VERSION 5.8 ;
BUSBITCHARS "[]" ;
DIVIDERCHAR "/" ;

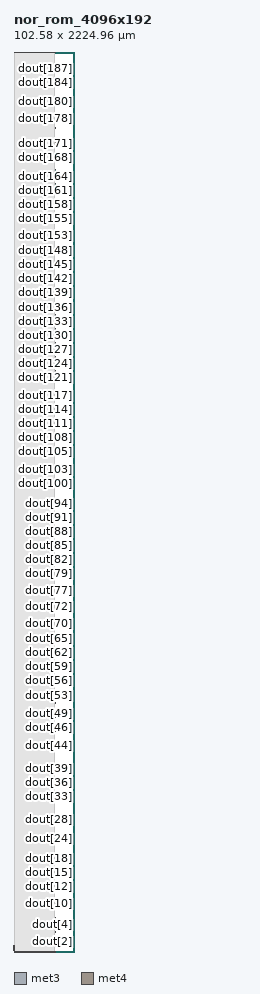
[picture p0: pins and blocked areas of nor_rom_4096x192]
MACRO nor_rom_4096x192
  CLASS BLOCK ;
  ORIGIN 0 0 ;
  SIZE 102.580 BY 2224.960 ;
  SYMMETRY X Y ;

  PIN clk
    DIRECTION INPUT ;
    USE CLOCK ;
    PORT
      LAYER met3 ;
        RECT -0.500 3.000 0.500 3.280 ;
    END
  END clk

  PIN ce
    DIRECTION INPUT ;
    USE SIGNAL ;
    PORT
      LAYER met3 ;
        RECT -0.500 4.000 0.500 4.280 ;
    END
  END ce

  PIN addr[0]
    DIRECTION INPUT ;
    USE SIGNAL ;
    PORT
      LAYER met3 ;
        RECT -0.500 5.000 0.500 5.280 ;
    END
  END addr[0]

  PIN addr[1]
    DIRECTION INPUT ;
    USE SIGNAL ;
    PORT
      LAYER met3 ;
        RECT -0.500 6.000 0.500 6.280 ;
    END
  END addr[1]

  PIN addr[2]
    DIRECTION INPUT ;
    USE SIGNAL ;
    PORT
      LAYER met3 ;
        RECT -0.500 7.000 0.500 7.280 ;
    END
  END addr[2]

  PIN addr[3]
    DIRECTION INPUT ;
    USE SIGNAL ;
    PORT
      LAYER met3 ;
        RECT -0.500 8.000 0.500 8.280 ;
    END
  END addr[3]

  PIN addr[4]
    DIRECTION INPUT ;
    USE SIGNAL ;
    PORT
      LAYER met3 ;
        RECT -0.500 9.000 0.500 9.280 ;
    END
  END addr[4]

  PIN addr[5]
    DIRECTION INPUT ;
    USE SIGNAL ;
    PORT
      LAYER met3 ;
        RECT -0.500 10.000 0.500 10.280 ;
    END
  END addr[5]

  PIN addr[6]
    DIRECTION INPUT ;
    USE SIGNAL ;
    PORT
      LAYER met3 ;
        RECT -0.500 11.000 0.500 11.280 ;
    END
  END addr[6]

  PIN addr[7]
    DIRECTION INPUT ;
    USE SIGNAL ;
    PORT
      LAYER met3 ;
        RECT -0.500 12.000 0.500 12.280 ;
    END
  END addr[7]

  PIN addr[8]
    DIRECTION INPUT ;
    USE SIGNAL ;
    PORT
      LAYER met3 ;
        RECT -0.500 13.000 0.500 13.280 ;
    END
  END addr[8]

  PIN addr[9]
    DIRECTION INPUT ;
    USE SIGNAL ;
    PORT
      LAYER met3 ;
        RECT -0.500 14.000 0.500 14.280 ;
    END
  END addr[9]

  PIN addr[10]
    DIRECTION INPUT ;
    USE SIGNAL ;
    PORT
      LAYER met3 ;
        RECT -0.500 15.000 0.500 15.280 ;
    END
  END addr[10]

  PIN addr[11]
    DIRECTION INPUT ;
    USE SIGNAL ;
    PORT
      LAYER met3 ;
        RECT -0.500 16.000 0.500 16.280 ;
    END
  END addr[11]

  PIN dout[0]
    DIRECTION OUTPUT ;
    USE SIGNAL ;
    PORT
      LAYER met3 ;
        RECT 102.080 3.000 103.080 3.280 ;
    END
  END dout[0]

  PIN dout[1]
    DIRECTION OUTPUT ;
    USE SIGNAL ;
    PORT
      LAYER met3 ;
        RECT 102.080 14.557 103.080 14.837 ;
    END
  END dout[1]

  PIN dout[2]
    DIRECTION OUTPUT ;
    USE SIGNAL ;
    PORT
      LAYER met3 ;
        RECT 102.080 26.114 103.080 26.394 ;
    END
  END dout[2]

  PIN dout[3]
    DIRECTION OUTPUT ;
    USE SIGNAL ;
    PORT
      LAYER met3 ;
        RECT 102.080 37.671 103.080 37.951 ;
    END
  END dout[3]

  PIN dout[4]
    DIRECTION OUTPUT ;
    USE SIGNAL ;
    PORT
      LAYER met3 ;
        RECT 102.080 49.228 103.080 49.508 ;
    END
  END dout[4]

  PIN dout[5]
    DIRECTION OUTPUT ;
    USE SIGNAL ;
    PORT
      LAYER met3 ;
        RECT 102.080 60.785 103.080 61.065 ;
    END
  END dout[5]

  PIN dout[6]
    DIRECTION OUTPUT ;
    USE SIGNAL ;
    PORT
      LAYER met3 ;
        RECT 102.080 72.343 103.080 72.623 ;
    END
  END dout[6]

  PIN dout[7]
    DIRECTION OUTPUT ;
    USE SIGNAL ;
    PORT
      LAYER met3 ;
        RECT 102.080 83.900 103.080 84.180 ;
    END
  END dout[7]

  PIN dout[8]
    DIRECTION OUTPUT ;
    USE SIGNAL ;
    PORT
      LAYER met3 ;
        RECT 102.080 95.457 103.080 95.737 ;
    END
  END dout[8]

  PIN dout[9]
    DIRECTION OUTPUT ;
    USE SIGNAL ;
    PORT
      LAYER met3 ;
        RECT 102.080 107.014 103.080 107.294 ;
    END
  END dout[9]

  PIN dout[10]
    DIRECTION OUTPUT ;
    USE SIGNAL ;
    PORT
      LAYER met3 ;
        RECT 102.080 118.571 103.080 118.851 ;
    END
  END dout[10]

  PIN dout[11]
    DIRECTION OUTPUT ;
    USE SIGNAL ;
    PORT
      LAYER met3 ;
        RECT 102.080 130.128 103.080 130.408 ;
    END
  END dout[11]

  PIN dout[12]
    DIRECTION OUTPUT ;
    USE SIGNAL ;
    PORT
      LAYER met3 ;
        RECT 102.080 141.685 103.080 141.965 ;
    END
  END dout[12]

  PIN dout[13]
    DIRECTION OUTPUT ;
    USE SIGNAL ;
    PORT
      LAYER met3 ;
        RECT 102.080 153.242 103.080 153.522 ;
    END
  END dout[13]

  PIN dout[14]
    DIRECTION OUTPUT ;
    USE SIGNAL ;
    PORT
      LAYER met3 ;
        RECT 102.080 164.799 103.080 165.079 ;
    END
  END dout[14]

  PIN dout[15]
    DIRECTION OUTPUT ;
    USE SIGNAL ;
    PORT
      LAYER met3 ;
        RECT 102.080 176.356 103.080 176.636 ;
    END
  END dout[15]

  PIN dout[16]
    DIRECTION OUTPUT ;
    USE SIGNAL ;
    PORT
      LAYER met3 ;
        RECT 102.080 187.913 103.080 188.193 ;
    END
  END dout[16]

  PIN dout[17]
    DIRECTION OUTPUT ;
    USE SIGNAL ;
    PORT
      LAYER met3 ;
        RECT 102.080 199.470 103.080 199.750 ;
    END
  END dout[17]

  PIN dout[18]
    DIRECTION OUTPUT ;
    USE SIGNAL ;
    PORT
      LAYER met3 ;
        RECT 102.080 211.028 103.080 211.308 ;
    END
  END dout[18]

  PIN dout[19]
    DIRECTION OUTPUT ;
    USE SIGNAL ;
    PORT
      LAYER met3 ;
        RECT 102.080 222.585 103.080 222.865 ;
    END
  END dout[19]

  PIN dout[20]
    DIRECTION OUTPUT ;
    USE SIGNAL ;
    PORT
      LAYER met3 ;
        RECT 102.080 234.142 103.080 234.422 ;
    END
  END dout[20]

  PIN dout[21]
    DIRECTION OUTPUT ;
    USE SIGNAL ;
    PORT
      LAYER met3 ;
        RECT 102.080 245.699 103.080 245.979 ;
    END
  END dout[21]

  PIN dout[22]
    DIRECTION OUTPUT ;
    USE SIGNAL ;
    PORT
      LAYER met3 ;
        RECT 102.080 257.256 103.080 257.536 ;
    END
  END dout[22]

  PIN dout[23]
    DIRECTION OUTPUT ;
    USE SIGNAL ;
    PORT
      LAYER met3 ;
        RECT 102.080 268.813 103.080 269.093 ;
    END
  END dout[23]

  PIN dout[24]
    DIRECTION OUTPUT ;
    USE SIGNAL ;
    PORT
      LAYER met3 ;
        RECT 102.080 280.370 103.080 280.650 ;
    END
  END dout[24]

  PIN dout[25]
    DIRECTION OUTPUT ;
    USE SIGNAL ;
    PORT
      LAYER met3 ;
        RECT 102.080 291.927 103.080 292.207 ;
    END
  END dout[25]

  PIN dout[26]
    DIRECTION OUTPUT ;
    USE SIGNAL ;
    PORT
      LAYER met3 ;
        RECT 102.080 303.484 103.080 303.764 ;
    END
  END dout[26]

  PIN dout[27]
    DIRECTION OUTPUT ;
    USE SIGNAL ;
    PORT
      LAYER met3 ;
        RECT 102.080 315.041 103.080 315.321 ;
    END
  END dout[27]

  PIN dout[28]
    DIRECTION OUTPUT ;
    USE SIGNAL ;
    PORT
      LAYER met3 ;
        RECT 102.080 326.598 103.080 326.878 ;
    END
  END dout[28]

  PIN dout[29]
    DIRECTION OUTPUT ;
    USE SIGNAL ;
    PORT
      LAYER met3 ;
        RECT 102.080 338.155 103.080 338.435 ;
    END
  END dout[29]

  PIN dout[30]
    DIRECTION OUTPUT ;
    USE SIGNAL ;
    PORT
      LAYER met3 ;
        RECT 102.080 349.712 103.080 349.992 ;
    END
  END dout[30]

  PIN dout[31]
    DIRECTION OUTPUT ;
    USE SIGNAL ;
    PORT
      LAYER met3 ;
        RECT 102.080 361.270 103.080 361.550 ;
    END
  END dout[31]

  PIN dout[32]
    DIRECTION OUTPUT ;
    USE SIGNAL ;
    PORT
      LAYER met3 ;
        RECT 102.080 372.827 103.080 373.107 ;
    END
  END dout[32]

  PIN dout[33]
    DIRECTION OUTPUT ;
    USE SIGNAL ;
    PORT
      LAYER met3 ;
        RECT 102.080 384.384 103.080 384.664 ;
    END
  END dout[33]

  PIN dout[34]
    DIRECTION OUTPUT ;
    USE SIGNAL ;
    PORT
      LAYER met3 ;
        RECT 102.080 395.941 103.080 396.221 ;
    END
  END dout[34]

  PIN dout[35]
    DIRECTION OUTPUT ;
    USE SIGNAL ;
    PORT
      LAYER met3 ;
        RECT 102.080 407.498 103.080 407.778 ;
    END
  END dout[35]

  PIN dout[36]
    DIRECTION OUTPUT ;
    USE SIGNAL ;
    PORT
      LAYER met3 ;
        RECT 102.080 419.055 103.080 419.335 ;
    END
  END dout[36]

  PIN dout[37]
    DIRECTION OUTPUT ;
    USE SIGNAL ;
    PORT
      LAYER met3 ;
        RECT 102.080 430.612 103.080 430.892 ;
    END
  END dout[37]

  PIN dout[38]
    DIRECTION OUTPUT ;
    USE SIGNAL ;
    PORT
      LAYER met3 ;
        RECT 102.080 442.169 103.080 442.449 ;
    END
  END dout[38]

  PIN dout[39]
    DIRECTION OUTPUT ;
    USE SIGNAL ;
    PORT
      LAYER met3 ;
        RECT 102.080 453.726 103.080 454.006 ;
    END
  END dout[39]

  PIN dout[40]
    DIRECTION OUTPUT ;
    USE SIGNAL ;
    PORT
      LAYER met3 ;
        RECT 102.080 465.283 103.080 465.563 ;
    END
  END dout[40]

  PIN dout[41]
    DIRECTION OUTPUT ;
    USE SIGNAL ;
    PORT
      LAYER met3 ;
        RECT 102.080 476.840 103.080 477.120 ;
    END
  END dout[41]

  PIN dout[42]
    DIRECTION OUTPUT ;
    USE SIGNAL ;
    PORT
      LAYER met3 ;
        RECT 102.080 488.397 103.080 488.677 ;
    END
  END dout[42]

  PIN dout[43]
    DIRECTION OUTPUT ;
    USE SIGNAL ;
    PORT
      LAYER met3 ;
        RECT 102.080 499.955 103.080 500.235 ;
    END
  END dout[43]

  PIN dout[44]
    DIRECTION OUTPUT ;
    USE SIGNAL ;
    PORT
      LAYER met3 ;
        RECT 102.080 511.512 103.080 511.792 ;
    END
  END dout[44]

  PIN dout[45]
    DIRECTION OUTPUT ;
    USE SIGNAL ;
    PORT
      LAYER met3 ;
        RECT 102.080 523.069 103.080 523.349 ;
    END
  END dout[45]

  PIN dout[46]
    DIRECTION OUTPUT ;
    USE SIGNAL ;
    PORT
      LAYER met3 ;
        RECT 102.080 534.626 103.080 534.906 ;
    END
  END dout[46]

  PIN dout[47]
    DIRECTION OUTPUT ;
    USE SIGNAL ;
    PORT
      LAYER met3 ;
        RECT 102.080 546.183 103.080 546.463 ;
    END
  END dout[47]

  PIN dout[48]
    DIRECTION OUTPUT ;
    USE SIGNAL ;
    PORT
      LAYER met3 ;
        RECT 102.080 557.740 103.080 558.020 ;
    END
  END dout[48]

  PIN dout[49]
    DIRECTION OUTPUT ;
    USE SIGNAL ;
    PORT
      LAYER met3 ;
        RECT 102.080 569.297 103.080 569.577 ;
    END
  END dout[49]

  PIN dout[50]
    DIRECTION OUTPUT ;
    USE SIGNAL ;
    PORT
      LAYER met3 ;
        RECT 102.080 580.854 103.080 581.134 ;
    END
  END dout[50]

  PIN dout[51]
    DIRECTION OUTPUT ;
    USE SIGNAL ;
    PORT
      LAYER met3 ;
        RECT 102.080 592.411 103.080 592.691 ;
    END
  END dout[51]

  PIN dout[52]
    DIRECTION OUTPUT ;
    USE SIGNAL ;
    PORT
      LAYER met3 ;
        RECT 102.080 603.968 103.080 604.248 ;
    END
  END dout[52]

  PIN dout[53]
    DIRECTION OUTPUT ;
    USE SIGNAL ;
    PORT
      LAYER met3 ;
        RECT 102.080 615.525 103.080 615.805 ;
    END
  END dout[53]

  PIN dout[54]
    DIRECTION OUTPUT ;
    USE SIGNAL ;
    PORT
      LAYER met3 ;
        RECT 102.080 627.082 103.080 627.362 ;
    END
  END dout[54]

  PIN dout[55]
    DIRECTION OUTPUT ;
    USE SIGNAL ;
    PORT
      LAYER met3 ;
        RECT 102.080 638.640 103.080 638.920 ;
    END
  END dout[55]

  PIN dout[56]
    DIRECTION OUTPUT ;
    USE SIGNAL ;
    PORT
      LAYER met3 ;
        RECT 102.080 650.197 103.080 650.477 ;
    END
  END dout[56]

  PIN dout[57]
    DIRECTION OUTPUT ;
    USE SIGNAL ;
    PORT
      LAYER met3 ;
        RECT 102.080 661.754 103.080 662.034 ;
    END
  END dout[57]

  PIN dout[58]
    DIRECTION OUTPUT ;
    USE SIGNAL ;
    PORT
      LAYER met3 ;
        RECT 102.080 673.311 103.080 673.591 ;
    END
  END dout[58]

  PIN dout[59]
    DIRECTION OUTPUT ;
    USE SIGNAL ;
    PORT
      LAYER met3 ;
        RECT 102.080 684.868 103.080 685.148 ;
    END
  END dout[59]

  PIN dout[60]
    DIRECTION OUTPUT ;
    USE SIGNAL ;
    PORT
      LAYER met3 ;
        RECT 102.080 696.425 103.080 696.705 ;
    END
  END dout[60]

  PIN dout[61]
    DIRECTION OUTPUT ;
    USE SIGNAL ;
    PORT
      LAYER met3 ;
        RECT 102.080 707.982 103.080 708.262 ;
    END
  END dout[61]

  PIN dout[62]
    DIRECTION OUTPUT ;
    USE SIGNAL ;
    PORT
      LAYER met3 ;
        RECT 102.080 719.539 103.080 719.819 ;
    END
  END dout[62]

  PIN dout[63]
    DIRECTION OUTPUT ;
    USE SIGNAL ;
    PORT
      LAYER met3 ;
        RECT 102.080 731.096 103.080 731.376 ;
    END
  END dout[63]

  PIN dout[64]
    DIRECTION OUTPUT ;
    USE SIGNAL ;
    PORT
      LAYER met3 ;
        RECT 102.080 742.653 103.080 742.933 ;
    END
  END dout[64]

  PIN dout[65]
    DIRECTION OUTPUT ;
    USE SIGNAL ;
    PORT
      LAYER met3 ;
        RECT 102.080 754.210 103.080 754.490 ;
    END
  END dout[65]

  PIN dout[66]
    DIRECTION OUTPUT ;
    USE SIGNAL ;
    PORT
      LAYER met3 ;
        RECT 102.080 765.767 103.080 766.047 ;
    END
  END dout[66]

  PIN dout[67]
    DIRECTION OUTPUT ;
    USE SIGNAL ;
    PORT
      LAYER met3 ;
        RECT 102.080 777.325 103.080 777.605 ;
    END
  END dout[67]

  PIN dout[68]
    DIRECTION OUTPUT ;
    USE SIGNAL ;
    PORT
      LAYER met3 ;
        RECT 102.080 788.882 103.080 789.162 ;
    END
  END dout[68]

  PIN dout[69]
    DIRECTION OUTPUT ;
    USE SIGNAL ;
    PORT
      LAYER met3 ;
        RECT 102.080 800.439 103.080 800.719 ;
    END
  END dout[69]

  PIN dout[70]
    DIRECTION OUTPUT ;
    USE SIGNAL ;
    PORT
      LAYER met3 ;
        RECT 102.080 811.996 103.080 812.276 ;
    END
  END dout[70]

  PIN dout[71]
    DIRECTION OUTPUT ;
    USE SIGNAL ;
    PORT
      LAYER met3 ;
        RECT 102.080 823.553 103.080 823.833 ;
    END
  END dout[71]

  PIN dout[72]
    DIRECTION OUTPUT ;
    USE SIGNAL ;
    PORT
      LAYER met3 ;
        RECT 102.080 835.110 103.080 835.390 ;
    END
  END dout[72]

  PIN dout[73]
    DIRECTION OUTPUT ;
    USE SIGNAL ;
    PORT
      LAYER met3 ;
        RECT 102.080 846.667 103.080 846.947 ;
    END
  END dout[73]

  PIN dout[74]
    DIRECTION OUTPUT ;
    USE SIGNAL ;
    PORT
      LAYER met3 ;
        RECT 102.080 858.224 103.080 858.504 ;
    END
  END dout[74]

  PIN dout[75]
    DIRECTION OUTPUT ;
    USE SIGNAL ;
    PORT
      LAYER met3 ;
        RECT 102.080 869.781 103.080 870.061 ;
    END
  END dout[75]

  PIN dout[76]
    DIRECTION OUTPUT ;
    USE SIGNAL ;
    PORT
      LAYER met3 ;
        RECT 102.080 881.338 103.080 881.618 ;
    END
  END dout[76]

  PIN dout[77]
    DIRECTION OUTPUT ;
    USE SIGNAL ;
    PORT
      LAYER met3 ;
        RECT 102.080 892.895 103.080 893.175 ;
    END
  END dout[77]

  PIN dout[78]
    DIRECTION OUTPUT ;
    USE SIGNAL ;
    PORT
      LAYER met3 ;
        RECT 102.080 904.452 103.080 904.732 ;
    END
  END dout[78]

  PIN dout[79]
    DIRECTION OUTPUT ;
    USE SIGNAL ;
    PORT
      LAYER met3 ;
        RECT 102.080 916.010 103.080 916.290 ;
    END
  END dout[79]

  PIN dout[80]
    DIRECTION OUTPUT ;
    USE SIGNAL ;
    PORT
      LAYER met3 ;
        RECT 102.080 927.567 103.080 927.847 ;
    END
  END dout[80]

  PIN dout[81]
    DIRECTION OUTPUT ;
    USE SIGNAL ;
    PORT
      LAYER met3 ;
        RECT 102.080 939.124 103.080 939.404 ;
    END
  END dout[81]

  PIN dout[82]
    DIRECTION OUTPUT ;
    USE SIGNAL ;
    PORT
      LAYER met3 ;
        RECT 102.080 950.681 103.080 950.961 ;
    END
  END dout[82]

  PIN dout[83]
    DIRECTION OUTPUT ;
    USE SIGNAL ;
    PORT
      LAYER met3 ;
        RECT 102.080 962.238 103.080 962.518 ;
    END
  END dout[83]

  PIN dout[84]
    DIRECTION OUTPUT ;
    USE SIGNAL ;
    PORT
      LAYER met3 ;
        RECT 102.080 973.795 103.080 974.075 ;
    END
  END dout[84]

  PIN dout[85]
    DIRECTION OUTPUT ;
    USE SIGNAL ;
    PORT
      LAYER met3 ;
        RECT 102.080 985.352 103.080 985.632 ;
    END
  END dout[85]

  PIN dout[86]
    DIRECTION OUTPUT ;
    USE SIGNAL ;
    PORT
      LAYER met3 ;
        RECT 102.080 996.909 103.080 997.189 ;
    END
  END dout[86]

  PIN dout[87]
    DIRECTION OUTPUT ;
    USE SIGNAL ;
    PORT
      LAYER met3 ;
        RECT 102.080 1008.466 103.080 1008.746 ;
    END
  END dout[87]

  PIN dout[88]
    DIRECTION OUTPUT ;
    USE SIGNAL ;
    PORT
      LAYER met3 ;
        RECT 102.080 1020.023 103.080 1020.303 ;
    END
  END dout[88]

  PIN dout[89]
    DIRECTION OUTPUT ;
    USE SIGNAL ;
    PORT
      LAYER met3 ;
        RECT 102.080 1031.580 103.080 1031.860 ;
    END
  END dout[89]

  PIN dout[90]
    DIRECTION OUTPUT ;
    USE SIGNAL ;
    PORT
      LAYER met3 ;
        RECT 102.080 1043.138 103.080 1043.418 ;
    END
  END dout[90]

  PIN dout[91]
    DIRECTION OUTPUT ;
    USE SIGNAL ;
    PORT
      LAYER met3 ;
        RECT 102.080 1054.695 103.080 1054.975 ;
    END
  END dout[91]

  PIN dout[92]
    DIRECTION OUTPUT ;
    USE SIGNAL ;
    PORT
      LAYER met3 ;
        RECT 102.080 1066.252 103.080 1066.532 ;
    END
  END dout[92]

  PIN dout[93]
    DIRECTION OUTPUT ;
    USE SIGNAL ;
    PORT
      LAYER met3 ;
        RECT 102.080 1077.809 103.080 1078.089 ;
    END
  END dout[93]

  PIN dout[94]
    DIRECTION OUTPUT ;
    USE SIGNAL ;
    PORT
      LAYER met3 ;
        RECT 102.080 1089.366 103.080 1089.646 ;
    END
  END dout[94]

  PIN dout[95]
    DIRECTION OUTPUT ;
    USE SIGNAL ;
    PORT
      LAYER met3 ;
        RECT 102.080 1100.923 103.080 1101.203 ;
    END
  END dout[95]

  PIN dout[96]
    DIRECTION OUTPUT ;
    USE SIGNAL ;
    PORT
      LAYER met3 ;
        RECT 102.080 1112.480 103.080 1112.760 ;
    END
  END dout[96]

  PIN dout[97]
    DIRECTION OUTPUT ;
    USE SIGNAL ;
    PORT
      LAYER met3 ;
        RECT 102.080 1124.037 103.080 1124.317 ;
    END
  END dout[97]

  PIN dout[98]
    DIRECTION OUTPUT ;
    USE SIGNAL ;
    PORT
      LAYER met3 ;
        RECT 102.080 1135.594 103.080 1135.874 ;
    END
  END dout[98]

  PIN dout[99]
    DIRECTION OUTPUT ;
    USE SIGNAL ;
    PORT
      LAYER met3 ;
        RECT 102.080 1147.151 103.080 1147.431 ;
    END
  END dout[99]

  PIN dout[100]
    DIRECTION OUTPUT ;
    USE SIGNAL ;
    PORT
      LAYER met3 ;
        RECT 102.080 1158.708 103.080 1158.988 ;
    END
  END dout[100]

  PIN dout[101]
    DIRECTION OUTPUT ;
    USE SIGNAL ;
    PORT
      LAYER met3 ;
        RECT 102.080 1170.265 103.080 1170.545 ;
    END
  END dout[101]

  PIN dout[102]
    DIRECTION OUTPUT ;
    USE SIGNAL ;
    PORT
      LAYER met3 ;
        RECT 102.080 1181.822 103.080 1182.102 ;
    END
  END dout[102]

  PIN dout[103]
    DIRECTION OUTPUT ;
    USE SIGNAL ;
    PORT
      LAYER met3 ;
        RECT 102.080 1193.380 103.080 1193.660 ;
    END
  END dout[103]

  PIN dout[104]
    DIRECTION OUTPUT ;
    USE SIGNAL ;
    PORT
      LAYER met3 ;
        RECT 102.080 1204.937 103.080 1205.217 ;
    END
  END dout[104]

  PIN dout[105]
    DIRECTION OUTPUT ;
    USE SIGNAL ;
    PORT
      LAYER met3 ;
        RECT 102.080 1216.494 103.080 1216.774 ;
    END
  END dout[105]

  PIN dout[106]
    DIRECTION OUTPUT ;
    USE SIGNAL ;
    PORT
      LAYER met3 ;
        RECT 102.080 1228.051 103.080 1228.331 ;
    END
  END dout[106]

  PIN dout[107]
    DIRECTION OUTPUT ;
    USE SIGNAL ;
    PORT
      LAYER met3 ;
        RECT 102.080 1239.608 103.080 1239.888 ;
    END
  END dout[107]

  PIN dout[108]
    DIRECTION OUTPUT ;
    USE SIGNAL ;
    PORT
      LAYER met3 ;
        RECT 102.080 1251.165 103.080 1251.445 ;
    END
  END dout[108]

  PIN dout[109]
    DIRECTION OUTPUT ;
    USE SIGNAL ;
    PORT
      LAYER met3 ;
        RECT 102.080 1262.722 103.080 1263.002 ;
    END
  END dout[109]

  PIN dout[110]
    DIRECTION OUTPUT ;
    USE SIGNAL ;
    PORT
      LAYER met3 ;
        RECT 102.080 1274.279 103.080 1274.559 ;
    END
  END dout[110]

  PIN dout[111]
    DIRECTION OUTPUT ;
    USE SIGNAL ;
    PORT
      LAYER met3 ;
        RECT 102.080 1285.836 103.080 1286.116 ;
    END
  END dout[111]

  PIN dout[112]
    DIRECTION OUTPUT ;
    USE SIGNAL ;
    PORT
      LAYER met3 ;
        RECT 102.080 1297.393 103.080 1297.673 ;
    END
  END dout[112]

  PIN dout[113]
    DIRECTION OUTPUT ;
    USE SIGNAL ;
    PORT
      LAYER met3 ;
        RECT 102.080 1308.950 103.080 1309.230 ;
    END
  END dout[113]

  PIN dout[114]
    DIRECTION OUTPUT ;
    USE SIGNAL ;
    PORT
      LAYER met3 ;
        RECT 102.080 1320.507 103.080 1320.787 ;
    END
  END dout[114]

  PIN dout[115]
    DIRECTION OUTPUT ;
    USE SIGNAL ;
    PORT
      LAYER met3 ;
        RECT 102.080 1332.065 103.080 1332.345 ;
    END
  END dout[115]

  PIN dout[116]
    DIRECTION OUTPUT ;
    USE SIGNAL ;
    PORT
      LAYER met3 ;
        RECT 102.080 1343.622 103.080 1343.902 ;
    END
  END dout[116]

  PIN dout[117]
    DIRECTION OUTPUT ;
    USE SIGNAL ;
    PORT
      LAYER met3 ;
        RECT 102.080 1355.179 103.080 1355.459 ;
    END
  END dout[117]

  PIN dout[118]
    DIRECTION OUTPUT ;
    USE SIGNAL ;
    PORT
      LAYER met3 ;
        RECT 102.080 1366.736 103.080 1367.016 ;
    END
  END dout[118]

  PIN dout[119]
    DIRECTION OUTPUT ;
    USE SIGNAL ;
    PORT
      LAYER met3 ;
        RECT 102.080 1378.293 103.080 1378.573 ;
    END
  END dout[119]

  PIN dout[120]
    DIRECTION OUTPUT ;
    USE SIGNAL ;
    PORT
      LAYER met3 ;
        RECT 102.080 1389.850 103.080 1390.130 ;
    END
  END dout[120]

  PIN dout[121]
    DIRECTION OUTPUT ;
    USE SIGNAL ;
    PORT
      LAYER met3 ;
        RECT 102.080 1401.407 103.080 1401.687 ;
    END
  END dout[121]

  PIN dout[122]
    DIRECTION OUTPUT ;
    USE SIGNAL ;
    PORT
      LAYER met3 ;
        RECT 102.080 1412.964 103.080 1413.244 ;
    END
  END dout[122]

  PIN dout[123]
    DIRECTION OUTPUT ;
    USE SIGNAL ;
    PORT
      LAYER met3 ;
        RECT 102.080 1424.521 103.080 1424.801 ;
    END
  END dout[123]

  PIN dout[124]
    DIRECTION OUTPUT ;
    USE SIGNAL ;
    PORT
      LAYER met3 ;
        RECT 102.080 1436.078 103.080 1436.358 ;
    END
  END dout[124]

  PIN dout[125]
    DIRECTION OUTPUT ;
    USE SIGNAL ;
    PORT
      LAYER met3 ;
        RECT 102.080 1447.635 103.080 1447.915 ;
    END
  END dout[125]

  PIN dout[126]
    DIRECTION OUTPUT ;
    USE SIGNAL ;
    PORT
      LAYER met3 ;
        RECT 102.080 1459.192 103.080 1459.472 ;
    END
  END dout[126]

  PIN dout[127]
    DIRECTION OUTPUT ;
    USE SIGNAL ;
    PORT
      LAYER met3 ;
        RECT 102.080 1470.750 103.080 1471.030 ;
    END
  END dout[127]

  PIN dout[128]
    DIRECTION OUTPUT ;
    USE SIGNAL ;
    PORT
      LAYER met3 ;
        RECT 102.080 1482.307 103.080 1482.587 ;
    END
  END dout[128]

  PIN dout[129]
    DIRECTION OUTPUT ;
    USE SIGNAL ;
    PORT
      LAYER met3 ;
        RECT 102.080 1493.864 103.080 1494.144 ;
    END
  END dout[129]

  PIN dout[130]
    DIRECTION OUTPUT ;
    USE SIGNAL ;
    PORT
      LAYER met3 ;
        RECT 102.080 1505.421 103.080 1505.701 ;
    END
  END dout[130]

  PIN dout[131]
    DIRECTION OUTPUT ;
    USE SIGNAL ;
    PORT
      LAYER met3 ;
        RECT 102.080 1516.978 103.080 1517.258 ;
    END
  END dout[131]

  PIN dout[132]
    DIRECTION OUTPUT ;
    USE SIGNAL ;
    PORT
      LAYER met3 ;
        RECT 102.080 1528.535 103.080 1528.815 ;
    END
  END dout[132]

  PIN dout[133]
    DIRECTION OUTPUT ;
    USE SIGNAL ;
    PORT
      LAYER met3 ;
        RECT 102.080 1540.092 103.080 1540.372 ;
    END
  END dout[133]

  PIN dout[134]
    DIRECTION OUTPUT ;
    USE SIGNAL ;
    PORT
      LAYER met3 ;
        RECT 102.080 1551.649 103.080 1551.929 ;
    END
  END dout[134]

  PIN dout[135]
    DIRECTION OUTPUT ;
    USE SIGNAL ;
    PORT
      LAYER met3 ;
        RECT 102.080 1563.206 103.080 1563.486 ;
    END
  END dout[135]

  PIN dout[136]
    DIRECTION OUTPUT ;
    USE SIGNAL ;
    PORT
      LAYER met3 ;
        RECT 102.080 1574.763 103.080 1575.043 ;
    END
  END dout[136]

  PIN dout[137]
    DIRECTION OUTPUT ;
    USE SIGNAL ;
    PORT
      LAYER met3 ;
        RECT 102.080 1586.320 103.080 1586.600 ;
    END
  END dout[137]

  PIN dout[138]
    DIRECTION OUTPUT ;
    USE SIGNAL ;
    PORT
      LAYER met3 ;
        RECT 102.080 1597.878 103.080 1598.158 ;
    END
  END dout[138]

  PIN dout[139]
    DIRECTION OUTPUT ;
    USE SIGNAL ;
    PORT
      LAYER met3 ;
        RECT 102.080 1609.435 103.080 1609.715 ;
    END
  END dout[139]

  PIN dout[140]
    DIRECTION OUTPUT ;
    USE SIGNAL ;
    PORT
      LAYER met3 ;
        RECT 102.080 1620.992 103.080 1621.272 ;
    END
  END dout[140]

  PIN dout[141]
    DIRECTION OUTPUT ;
    USE SIGNAL ;
    PORT
      LAYER met3 ;
        RECT 102.080 1632.549 103.080 1632.829 ;
    END
  END dout[141]

  PIN dout[142]
    DIRECTION OUTPUT ;
    USE SIGNAL ;
    PORT
      LAYER met3 ;
        RECT 102.080 1644.106 103.080 1644.386 ;
    END
  END dout[142]

  PIN dout[143]
    DIRECTION OUTPUT ;
    USE SIGNAL ;
    PORT
      LAYER met3 ;
        RECT 102.080 1655.663 103.080 1655.943 ;
    END
  END dout[143]

  PIN dout[144]
    DIRECTION OUTPUT ;
    USE SIGNAL ;
    PORT
      LAYER met3 ;
        RECT 102.080 1667.220 103.080 1667.500 ;
    END
  END dout[144]

  PIN dout[145]
    DIRECTION OUTPUT ;
    USE SIGNAL ;
    PORT
      LAYER met3 ;
        RECT 102.080 1678.777 103.080 1679.057 ;
    END
  END dout[145]

  PIN dout[146]
    DIRECTION OUTPUT ;
    USE SIGNAL ;
    PORT
      LAYER met3 ;
        RECT 102.080 1690.334 103.080 1690.614 ;
    END
  END dout[146]

  PIN dout[147]
    DIRECTION OUTPUT ;
    USE SIGNAL ;
    PORT
      LAYER met3 ;
        RECT 102.080 1701.891 103.080 1702.171 ;
    END
  END dout[147]

  PIN dout[148]
    DIRECTION OUTPUT ;
    USE SIGNAL ;
    PORT
      LAYER met3 ;
        RECT 102.080 1713.448 103.080 1713.728 ;
    END
  END dout[148]

  PIN dout[149]
    DIRECTION OUTPUT ;
    USE SIGNAL ;
    PORT
      LAYER met3 ;
        RECT 102.080 1725.005 103.080 1725.285 ;
    END
  END dout[149]

  PIN dout[150]
    DIRECTION OUTPUT ;
    USE SIGNAL ;
    PORT
      LAYER met3 ;
        RECT 102.080 1736.562 103.080 1736.842 ;
    END
  END dout[150]

  PIN dout[151]
    DIRECTION OUTPUT ;
    USE SIGNAL ;
    PORT
      LAYER met3 ;
        RECT 102.080 1748.120 103.080 1748.400 ;
    END
  END dout[151]

  PIN dout[152]
    DIRECTION OUTPUT ;
    USE SIGNAL ;
    PORT
      LAYER met3 ;
        RECT 102.080 1759.677 103.080 1759.957 ;
    END
  END dout[152]

  PIN dout[153]
    DIRECTION OUTPUT ;
    USE SIGNAL ;
    PORT
      LAYER met3 ;
        RECT 102.080 1771.234 103.080 1771.514 ;
    END
  END dout[153]

  PIN dout[154]
    DIRECTION OUTPUT ;
    USE SIGNAL ;
    PORT
      LAYER met3 ;
        RECT 102.080 1782.791 103.080 1783.071 ;
    END
  END dout[154]

  PIN dout[155]
    DIRECTION OUTPUT ;
    USE SIGNAL ;
    PORT
      LAYER met3 ;
        RECT 102.080 1794.348 103.080 1794.628 ;
    END
  END dout[155]

  PIN dout[156]
    DIRECTION OUTPUT ;
    USE SIGNAL ;
    PORT
      LAYER met3 ;
        RECT 102.080 1805.905 103.080 1806.185 ;
    END
  END dout[156]

  PIN dout[157]
    DIRECTION OUTPUT ;
    USE SIGNAL ;
    PORT
      LAYER met3 ;
        RECT 102.080 1817.462 103.080 1817.742 ;
    END
  END dout[157]

  PIN dout[158]
    DIRECTION OUTPUT ;
    USE SIGNAL ;
    PORT
      LAYER met3 ;
        RECT 102.080 1829.019 103.080 1829.299 ;
    END
  END dout[158]

  PIN dout[159]
    DIRECTION OUTPUT ;
    USE SIGNAL ;
    PORT
      LAYER met3 ;
        RECT 102.080 1840.576 103.080 1840.856 ;
    END
  END dout[159]

  PIN dout[160]
    DIRECTION OUTPUT ;
    USE SIGNAL ;
    PORT
      LAYER met3 ;
        RECT 102.080 1852.133 103.080 1852.413 ;
    END
  END dout[160]

  PIN dout[161]
    DIRECTION OUTPUT ;
    USE SIGNAL ;
    PORT
      LAYER met3 ;
        RECT 102.080 1863.690 103.080 1863.970 ;
    END
  END dout[161]

  PIN dout[162]
    DIRECTION OUTPUT ;
    USE SIGNAL ;
    PORT
      LAYER met3 ;
        RECT 102.080 1875.247 103.080 1875.527 ;
    END
  END dout[162]

  PIN dout[163]
    DIRECTION OUTPUT ;
    USE SIGNAL ;
    PORT
      LAYER met3 ;
        RECT 102.080 1886.805 103.080 1887.085 ;
    END
  END dout[163]

  PIN dout[164]
    DIRECTION OUTPUT ;
    USE SIGNAL ;
    PORT
      LAYER met3 ;
        RECT 102.080 1898.362 103.080 1898.642 ;
    END
  END dout[164]

  PIN dout[165]
    DIRECTION OUTPUT ;
    USE SIGNAL ;
    PORT
      LAYER met3 ;
        RECT 102.080 1909.919 103.080 1910.199 ;
    END
  END dout[165]

  PIN dout[166]
    DIRECTION OUTPUT ;
    USE SIGNAL ;
    PORT
      LAYER met3 ;
        RECT 102.080 1921.476 103.080 1921.756 ;
    END
  END dout[166]

  PIN dout[167]
    DIRECTION OUTPUT ;
    USE SIGNAL ;
    PORT
      LAYER met3 ;
        RECT 102.080 1933.033 103.080 1933.313 ;
    END
  END dout[167]

  PIN dout[168]
    DIRECTION OUTPUT ;
    USE SIGNAL ;
    PORT
      LAYER met3 ;
        RECT 102.080 1944.590 103.080 1944.870 ;
    END
  END dout[168]

  PIN dout[169]
    DIRECTION OUTPUT ;
    USE SIGNAL ;
    PORT
      LAYER met3 ;
        RECT 102.080 1956.147 103.080 1956.427 ;
    END
  END dout[169]

  PIN dout[170]
    DIRECTION OUTPUT ;
    USE SIGNAL ;
    PORT
      LAYER met3 ;
        RECT 102.080 1967.704 103.080 1967.984 ;
    END
  END dout[170]

  PIN dout[171]
    DIRECTION OUTPUT ;
    USE SIGNAL ;
    PORT
      LAYER met3 ;
        RECT 102.080 1979.261 103.080 1979.541 ;
    END
  END dout[171]

  PIN dout[172]
    DIRECTION OUTPUT ;
    USE SIGNAL ;
    PORT
      LAYER met3 ;
        RECT 102.080 1990.818 103.080 1991.098 ;
    END
  END dout[172]

  PIN dout[173]
    DIRECTION OUTPUT ;
    USE SIGNAL ;
    PORT
      LAYER met3 ;
        RECT 102.080 2002.375 103.080 2002.655 ;
    END
  END dout[173]

  PIN dout[174]
    DIRECTION OUTPUT ;
    USE SIGNAL ;
    PORT
      LAYER met3 ;
        RECT 102.080 2013.932 103.080 2014.212 ;
    END
  END dout[174]

  PIN dout[175]
    DIRECTION OUTPUT ;
    USE SIGNAL ;
    PORT
      LAYER met3 ;
        RECT 102.080 2025.490 103.080 2025.770 ;
    END
  END dout[175]

  PIN dout[176]
    DIRECTION OUTPUT ;
    USE SIGNAL ;
    PORT
      LAYER met3 ;
        RECT 102.080 2037.047 103.080 2037.327 ;
    END
  END dout[176]

  PIN dout[177]
    DIRECTION OUTPUT ;
    USE SIGNAL ;
    PORT
      LAYER met3 ;
        RECT 102.080 2048.604 103.080 2048.884 ;
    END
  END dout[177]

  PIN dout[178]
    DIRECTION OUTPUT ;
    USE SIGNAL ;
    PORT
      LAYER met3 ;
        RECT 102.080 2060.161 103.080 2060.441 ;
    END
  END dout[178]

  PIN dout[179]
    DIRECTION OUTPUT ;
    USE SIGNAL ;
    PORT
      LAYER met3 ;
        RECT 102.080 2071.718 103.080 2071.998 ;
    END
  END dout[179]

  PIN dout[180]
    DIRECTION OUTPUT ;
    USE SIGNAL ;
    PORT
      LAYER met3 ;
        RECT 102.080 2083.275 103.080 2083.555 ;
    END
  END dout[180]

  PIN dout[181]
    DIRECTION OUTPUT ;
    USE SIGNAL ;
    PORT
      LAYER met3 ;
        RECT 102.080 2094.832 103.080 2095.112 ;
    END
  END dout[181]

  PIN dout[182]
    DIRECTION OUTPUT ;
    USE SIGNAL ;
    PORT
      LAYER met3 ;
        RECT 102.080 2106.389 103.080 2106.669 ;
    END
  END dout[182]

  PIN dout[183]
    DIRECTION OUTPUT ;
    USE SIGNAL ;
    PORT
      LAYER met3 ;
        RECT 102.080 2117.946 103.080 2118.226 ;
    END
  END dout[183]

  PIN dout[184]
    DIRECTION OUTPUT ;
    USE SIGNAL ;
    PORT
      LAYER met3 ;
        RECT 102.080 2129.503 103.080 2129.783 ;
    END
  END dout[184]

  PIN dout[185]
    DIRECTION OUTPUT ;
    USE SIGNAL ;
    PORT
      LAYER met3 ;
        RECT 102.080 2141.060 103.080 2141.340 ;
    END
  END dout[185]

  PIN dout[186]
    DIRECTION OUTPUT ;
    USE SIGNAL ;
    PORT
      LAYER met3 ;
        RECT 102.080 2152.617 103.080 2152.898 ;
    END
  END dout[186]

  PIN dout[187]
    DIRECTION OUTPUT ;
    USE SIGNAL ;
    PORT
      LAYER met3 ;
        RECT 102.080 2164.175 103.080 2164.455 ;
    END
  END dout[187]

  PIN dout[188]
    DIRECTION OUTPUT ;
    USE SIGNAL ;
    PORT
      LAYER met3 ;
        RECT 102.080 2175.732 103.080 2176.012 ;
    END
  END dout[188]

  PIN dout[189]
    DIRECTION OUTPUT ;
    USE SIGNAL ;
    PORT
      LAYER met3 ;
        RECT 102.080 2187.289 103.080 2187.569 ;
    END
  END dout[189]

  PIN dout[190]
    DIRECTION OUTPUT ;
    USE SIGNAL ;
    PORT
      LAYER met3 ;
        RECT 102.080 2198.846 103.080 2199.126 ;
    END
  END dout[190]

  PIN dout[191]
    DIRECTION OUTPUT ;
    USE SIGNAL ;
    PORT
      LAYER met3 ;
        RECT 102.080 2210.403 103.080 2210.683 ;
    END
  END dout[191]

  PIN VDD
    DIRECTION INOUT ;
    USE POWER ;
    PORT
      LAYER met4 ;
        RECT 0.000 2223.960 102.580 2224.960 ;
    END
  END VDD

  PIN VSS
    DIRECTION INOUT ;
    USE GROUND ;
    PORT
      LAYER met4 ;
        RECT 0.000 0.000 102.580 1.000 ;
    END
  END VSS

  OBS
    LAYER met1 ;
      RECT 2.000 2.000 100.580 2222.960 ;
    LAYER met2 ;
      RECT 2.000 2.000 100.580 2222.960 ;
  END

END nor_rom_4096x192

END LIBRARY
